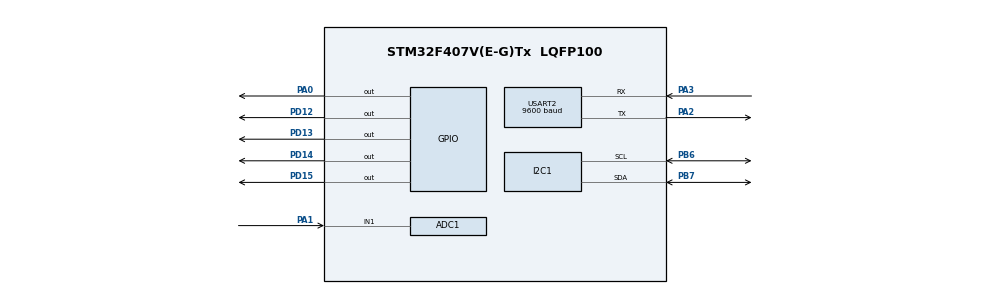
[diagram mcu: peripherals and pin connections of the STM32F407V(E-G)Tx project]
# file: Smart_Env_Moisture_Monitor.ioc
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ADC1.Channel-0\#ChannelRegularConversion=ADC_CHANNEL_1
ADC1.NbrOfConversionFlag=1
ADC1.Rank-0\#ChannelRegularConversion=1
ADC1.SamplingTime-0\#ChannelRegularConversion=ADC_SAMPLETIME_3CYCLES
ADC1.master=1
Mcu.Family=STM32F4
Mcu.Name=STM32F407V(E-G)Tx
Mcu.Package=LQFP100
NVIC.PriorityGroup=NVIC_PRIORITYGROUP_0
PA0-WKUP.Signal=GPIO_Output
PA1.Signal=ADCx_IN1
PA2.Mode=Asynchronous
PA2.Signal=USART2_TX
PA3.Mode=Asynchronous
PA3.Signal=USART2_RX
PB6.Mode=I2C
PB6.Signal=I2C1_SCL
PB7.Mode=I2C
PB7.Signal=I2C1_SDA
PD12.Signal=GPIO_Output
PD13.Signal=GPIO_Output
PD14.Signal=GPIO_Output
PD15.Signal=GPIO_Output
ProjectManager.HeapSize=0x200
ProjectManager.StackSize=0x400
ProjectManager.TargetToolchain=STM32CubeIDE
RCC.48MHZClocksFreq_Value=14285714.285714285
RCC.AHBFreq_Value=25000000
RCC.APB1CLKDivider=RCC_HCLK_DIV4
RCC.APB1Freq_Value=6250000
RCC.APB1TimFreq_Value=12500000
RCC.APB2CLKDivider=RCC_HCLK_DIV2
RCC.APB2Freq_Value=12500000
RCC.APB2TimFreq_Value=25000000
RCC.CortexFreq_Value=25000000
RCC.HCLKFreq_Value=25000000
RCC.HSE_VALUE=8000000
RCC.HSI_VALUE=16000000
RCC.LSE_VALUE=32768
RCC.PLLM=8
RCC.PLLN=50
RCC.PLLP=RCC_PLLP_DIV4
RCC.PLLQ=7
RCC.SYSCLKFreq_VALUE=25000000
RCC.SYSCLKSource=RCC_SYSCLKSOURCE_PLLCLK
RCC.VCOOutputFreq_Value=100000000
SH.ADCx_IN1.0=ADC1_IN1,IN1
USART2.BaudRate=9600
USART2.VirtualMode=VM_ASYNC
board=STM32F407G-DISC1

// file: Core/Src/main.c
/* USER CODE BEGIN Header */
/**
  ******************************************************************************
  * @file           : main.c
  * @brief          : Main program body
  ******************************************************************************
  * @attention
  *
  * Copyright (c) 2025 STMicroelectronics.
  * All rights reserved.
  *
  * This software is licensed under terms that can be found in the LICENSE file
  * in the root directory of this software component.
  * If no LICENSE file comes with this software, it is provided AS-IS.
  *
  ******************************************************************************
  */
/* USER CODE END Header */
#include "main.h"
#include "dht11.h"
#include "buzzer.h"
#include "led.h"
#include "MQ2.h"
#include "lcd.h"
#include<stdio.h>
#include<string.h>

ADC_HandleTypeDef hadc1;

I2C_HandleTypeDef hi2c1;

UART_HandleTypeDef huart2;

void SystemClock_Config(void);
static void MX_GPIO_Init(void);
static void MX_I2C1_Init(void);
static void MX_ADC1_Init(void);
static void MX_USART2_UART_Init(void);

int main(void)
{

  /* MCU Configuration--------------------------------------------------------*/

  /* Reset of all peripherals, Initializes the Flash interface and the Systick. */
  HAL_Init();

  /* USER CODE BEGIN Init */
DHT11_Init();
  /* USER CODE END Init */

  /* Configure the system clock */
  SystemClock_Config();

  /* Initialize all configured peripherals */
  MX_GPIO_Init();
  MX_I2C1_Init();
  MX_ADC1_Init();
  MX_USART2_UART_Init();
  /* USER CODE BEGIN 2 */
char buf[20];
char uart_buf[30];
uint8_t  temperature=0;
uint8_t humidity=0;
  /* USER CODE END 2 */
  if (!lcd16x2_i2c_init(&hi2c1))
    {
        // LCD not detected
        while(1);
     }
  while (1)
  {
	    Smoke_Monitor_Task();
	    Led_Alert();
	    Buzzer_Alert();
	    HAL_Delay(2000);

	     lcd16x2_i2c_clear();

        if (DHT11_Read(&temperature, &humidity) == 0)
        {
            sprintf(buf, "Tempreture:%d C", temperature);
            lcd16x2_i2c_setCursor(0, 0);
            lcd16x2_i2c_printf(buf);

            sprintf(buf, "Humidity :%d %%", humidity);
            lcd16x2_i2c_setCursor(1, 0);
            lcd16x2_i2c_printf(buf);
            sprintf(uart_buf,"Tempreture:%dC Hum:%d%%\r\n",temperature,humidity);

           	          HAL_UART_Transmit(&huart2,(uint8_t *)uart_buf,strlen(uart_buf),HAL_MAX_DELAY);
           	      }
           	      else
           	      {
           	          /* Error case */
           	          HAL_UART_Transmit(&huart2, (uint8_t *)"DHT11 ERROR\r\n",13, HAL_MAX_DELAY);
           	      }

           	      HAL_Delay(2000);
	    // LCD refresh interval
  }
}

void SystemClock_Config(void)
{
  RCC_OscInitTypeDef RCC_OscInitStruct = {0};
  RCC_ClkInitTypeDef RCC_ClkInitStruct = {0};

  /** Configure the main internal regulator output voltage
  */
  __HAL_RCC_PWR_CLK_ENABLE();
  __HAL_PWR_VOLTAGESCALING_CONFIG(PWR_REGULATOR_VOLTAGE_SCALE1);

  /** Initializes the RCC Oscillators according to the specified parameters
  * in the RCC_OscInitTypeDef structure.
  */
  RCC_OscInitStruct.OscillatorType = RCC_OSCILLATORTYPE_HSI;
  RCC_OscInitStruct.HSIState = RCC_HSI_ON;
  RCC_OscInitStruct.HSICalibrationValue = RCC_HSICALIBRATION_DEFAULT;
  RCC_OscInitStruct.PLL.PLLState = RCC_PLL_ON;
  RCC_OscInitStruct.PLL.PLLSource = RCC_PLLSOURCE_HSI;
  RCC_OscInitStruct.PLL.PLLM = 8;
  RCC_OscInitStruct.PLL.PLLN = 50;
  RCC_OscInitStruct.PLL.PLLP = RCC_PLLP_DIV2;
  RCC_OscInitStruct.PLL.PLLQ = 7;
  if (HAL_RCC_OscConfig(&RCC_OscInitStruct) != HAL_OK)
  {
    Error_Handler();
  }

  /** Initializes the CPU, AHB and APB buses clocks
  */
  RCC_ClkInitStruct.ClockType = RCC_CLOCKTYPE_HCLK|RCC_CLOCKTYPE_SYSCLK
                              |RCC_CLOCKTYPE_PCLK1|RCC_CLOCKTYPE_PCLK2;
  RCC_ClkInitStruct.SYSCLKSource = RCC_SYSCLKSOURCE_PLLCLK;
  RCC_ClkInitStruct.AHBCLKDivider = RCC_SYSCLK_DIV1;
  RCC_ClkInitStruct.APB1CLKDivider = RCC_HCLK_DIV4;
  RCC_ClkInitStruct.APB2CLKDivider = RCC_HCLK_DIV2;

  if (HAL_RCC_ClockConfig(&RCC_ClkInitStruct, FLASH_LATENCY_1) != HAL_OK)
  {
    Error_Handler();
  }
}

static void MX_ADC1_Init(void)
{

  ADC_ChannelConfTypeDef sConfig = {0};

  /** Configure the global features of the ADC (Clock, Resolution, Data Alignment and number of conversion)
  */
  hadc1.Instance = ADC1;
  hadc1.Init.ClockPrescaler = ADC_CLOCK_SYNC_PCLK_DIV2;
  hadc1.Init.Resolution = ADC_RESOLUTION_12B;
  hadc1.Init.ScanConvMode = DISABLE;
  hadc1.Init.ContinuousConvMode = DISABLE;
  hadc1.Init.DiscontinuousConvMode = DISABLE;
  hadc1.Init.ExternalTrigConvEdge = ADC_EXTERNALTRIGCONVEDGE_NONE;
  hadc1.Init.ExternalTrigConv = ADC_SOFTWARE_START;
  hadc1.Init.DataAlign = ADC_DATAALIGN_RIGHT;
  hadc1.Init.NbrOfConversion = 1;
  hadc1.Init.DMAContinuousRequests = DISABLE;
  hadc1.Init.EOCSelection = ADC_EOC_SINGLE_CONV;
  if (HAL_ADC_Init(&hadc1) != HAL_OK)
  {
    Error_Handler();
  }

  /** Configure for the selected ADC regular channel its corresponding rank in the sequencer and its sample time.
  */
  sConfig.Channel = ADC_CHANNEL_1;
  sConfig.Rank = 1;
  sConfig.SamplingTime = ADC_SAMPLETIME_3CYCLES;
  if (HAL_ADC_ConfigChannel(&hadc1, &sConfig) != HAL_OK)
  {
    Error_Handler();
  }

}

static void MX_I2C1_Init(void)
{

  hi2c1.Instance = I2C1;
  hi2c1.Init.ClockSpeed = 100000;
  hi2c1.Init.DutyCycle = I2C_DUTYCYCLE_2;
  hi2c1.Init.OwnAddress1 = 0;
  hi2c1.Init.AddressingMode = I2C_ADDRESSINGMODE_7BIT;
  hi2c1.Init.DualAddressMode = I2C_DUALADDRESS_DISABLE;
  hi2c1.Init.OwnAddress2 = 0;
  hi2c1.Init.GeneralCallMode = I2C_GENERALCALL_DISABLE;
  hi2c1.Init.NoStretchMode = I2C_NOSTRETCH_DISABLE;
  if (HAL_I2C_Init(&hi2c1) != HAL_OK)
  {
    Error_Handler();
  }

}

static void MX_USART2_UART_Init(void)
{

  huart2.Instance = USART2;
  huart2.Init.BaudRate = 9600;
  huart2.Init.WordLength = UART_WORDLENGTH_8B;
  huart2.Init.StopBits = UART_STOPBITS_1;
  huart2.Init.Parity = UART_PARITY_NONE;
  huart2.Init.Mode = UART_MODE_TX_RX;
  huart2.Init.HwFlowCtl = UART_HWCONTROL_NONE;
  huart2.Init.OverSampling = UART_OVERSAMPLING_16;
  if (HAL_UART_Init(&huart2) != HAL_OK)
  {
    Error_Handler();
  }

}

static void MX_GPIO_Init(void)
{
  GPIO_InitTypeDef GPIO_InitStruct = {0};

  /* GPIO Ports Clock Enable */
  __HAL_RCC_GPIOA_CLK_ENABLE();
  __HAL_RCC_GPIOD_CLK_ENABLE();
  __HAL_RCC_GPIOB_CLK_ENABLE();

  /*Configure GPIO pin Output Level */
  HAL_GPIO_WritePin(GPIOD, GPIO_PIN_12|GPIO_PIN_13|GPIO_PIN_14|GPIO_PIN_15, GPIO_PIN_RESET);

  /*Configure GPIO pins : PD12 PD13 PD14 PD15 */
  GPIO_InitStruct.Pin = GPIO_PIN_12|GPIO_PIN_13|GPIO_PIN_14|GPIO_PIN_15;
  GPIO_InitStruct.Mode = GPIO_MODE_OUTPUT_PP;
  GPIO_InitStruct.Pull = GPIO_NOPULL;
  GPIO_InitStruct.Speed = GPIO_SPEED_FREQ_LOW;
  HAL_GPIO_Init(GPIOD, &GPIO_InitStruct);

}

void Error_Handler(void)
{
  __disable_irq();
  while (1)
  {
  }
}
